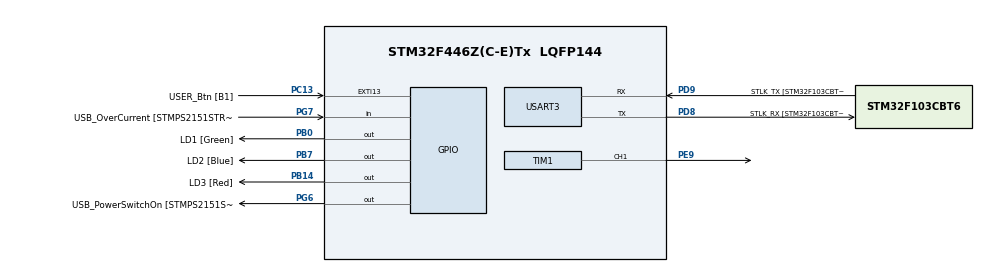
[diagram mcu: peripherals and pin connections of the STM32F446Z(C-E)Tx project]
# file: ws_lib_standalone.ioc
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Dma.Request0=TIM1_CH1
Dma.TIM1_CH1.0.Direction=DMA_PERIPH_TO_MEMORY
Dma.TIM1_CH1.0.FIFOMode=DMA_FIFOMODE_DISABLE
Dma.TIM1_CH1.0.Instance=DMA2_Stream1
Dma.TIM1_CH1.0.MemDataAlignment=DMA_MDATAALIGN_HALFWORD
Dma.TIM1_CH1.0.MemInc=DMA_MINC_ENABLE
Dma.TIM1_CH1.0.Mode=DMA_NORMAL
Dma.TIM1_CH1.0.PeriphDataAlignment=DMA_PDATAALIGN_HALFWORD
Dma.TIM1_CH1.0.PeriphInc=DMA_PINC_DISABLE
Dma.TIM1_CH1.0.Priority=DMA_PRIORITY_LOW
Mcu.Family=STM32F4
Mcu.Name=STM32F446Z(C-E)Tx
Mcu.Package=LQFP144
NVIC.DMA2_Stream1_IRQn=true\:0\:0\:false\:false\:true\:false\:true
NVIC.PriorityGroup=NVIC_PRIORITYGROUP_4
PA10.GPIO_Label=USB_ID
PA10.Signal=USB_OTG_FS_ID
PA11.GPIO_Label=USB_DM
PA11.Signal=USB_OTG_FS_DM
PA12.GPIO_Label=USB_DP
PA12.Signal=USB_OTG_FS_DP
PA13.GPIO_Label=TMS
PA13.Mode=Serial_Wire
PA13.Signal=SYS_JTMS-SWDIO
PA14.GPIO_Label=TCK
PA14.Mode=Serial_Wire
PA14.Signal=SYS_JTCK-SWCLK
PA8.GPIO_Label=USB_SOF [TP1]
PA8.Signal=USB_OTG_FS_SOF
PA9.GPIO_Label=USB_VBUS
PA9.Signal=USB_OTG_FS_VBUS
PB0.GPIO_Label=LD1 [Green]
PB0.Signal=GPIO_Output
PB14.GPIO_Label=LD3 [Red]
PB14.Signal=GPIO_Output
PB7.GPIO_Label=LD2 [Blue]
PB7.Signal=GPIO_Output
PC13.GPIO_Label=USER_Btn [B1]
PC13.Signal=GPXTI13
PC14-OSC32_IN.Mode=LSE-External-Oscillator
PC14-OSC32_IN.Signal=RCC_OSC32_IN
PC15-OSC32_OUT.Mode=LSE-External-Oscillator
PC15-OSC32_OUT.Signal=RCC_OSC32_OUT
PD8.GPIO_Label=STLK_RX [STM32F103CBT6_PA3]
PD8.Mode=Asynchronous
PD8.Signal=USART3_TX
PD9.GPIO_Label=STLK_TX [STM32F103CBT6_PA2]
PD9.Mode=Asynchronous
PD9.Signal=USART3_RX
PE9.Signal=S_TIM1_CH1
PG6.GPIO_Label=USB_PowerSwitchOn [STMPS2151STR_EN]
PG6.Signal=GPIO_Output
PG7.GPIO_Label=USB_OverCurrent [STMPS2151STR_FAULT]
PG7.Signal=GPIO_Input
PH0-OSC_IN.GPIO_Label=MCO [STM32F103CBT6_PA8]
PH0-OSC_IN.Mode=HSE-External-Clock-Source
PH0-OSC_IN.Signal=RCC_OSC_IN
PH1-OSC_OUT.Mode=HSE-External-Clock-Source
PH1-OSC_OUT.Signal=RCC_OSC_OUT
ProjectManager.HeapSize=0x200
ProjectManager.StackSize=0x400
ProjectManager.TargetToolchain=STM32CubeIDE
RCC.48MHZClocksFreq_Value=24000000
RCC.AHBFreq_Value=160000000
RCC.APB1CLKDivider=RCC_HCLK_DIV4
RCC.APB1Freq_Value=40000000
RCC.APB1TimFreq_Value=80000000
RCC.APB2CLKDivider=RCC_HCLK_DIV2
RCC.APB2Freq_Value=80000000
RCC.APB2TimFreq_Value=160000000
RCC.CortexFreq_Value=160000000
RCC.HCLKFreq_Value=160000000
RCC.HSE_VALUE=8000000
RCC.HSI_VALUE=16000000
RCC.PLLM=4
RCC.PLLMUL=RCC_PLL_MUL9
RCC.PLLN=160
RCC.PLLQ=7
RCC.PLLSourceVirtual=RCC_PLLSOURCE_HSE
RCC.PRESCALERUSB=RCC_USBCLKSOURCE_PLL_DIV1_5
RCC.SYSCLKFreq_VALUE=160000000
RCC.SYSCLKSource=RCC_SYSCLKSOURCE_PLLCLK
RCC.SYSCLKSourceVirtual=RCC_SYSCLKSOURCE_PLLCLK
RCC.USBFreq_Value=45714285.71428572
RCC.VCOOutputFreq_Value=320000000
SH.S_TIM1_CH1.0=TIM1_CH1,PWM Generation1 CH1
TIM1.Channel-PWM\ Generation1\ CH1=TIM_CHANNEL_1
USART3.VirtualMode=VM_ASYNC
VP_TIM1_VS_ClockSourceINT.Mode=Internal
board=NUCLEO-F446ZE

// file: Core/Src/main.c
/* USER CODE BEGIN Header */
/**
  ******************************************************************************
  * @file           : main.c
  * @brief          : Main program body
  ******************************************************************************
  * @attention
  *
  * <h2><center>&copy; Copyright (c) 2020 STMicroelectronics.
  * All rights reserved.</center></h2>
  *
  * This software component is licensed by ST under BSD 3-Clause license,
  * the "License"; You may not use this file except in compliance with the
  * License. You may obtain a copy of the License at:
  *                        opensource.org/licenses/BSD-3-Clause
  *
  ******************************************************************************
  */
/* USER CODE END Header */

#include "main.h"

/* USER CODE BEGIN Includes */
#include "stdio.h"
#include "WS2812_Lib.h"
/* USER CODE END Includes */

TIM_HandleTypeDef htim1;
DMA_HandleTypeDef hdma_tim1_ch1;

UART_HandleTypeDef huart3;

void SystemClock_Config(void);
static void MX_GPIO_Init(void);
static void MX_DMA_Init(void);
static void MX_USART3_UART_Init(void);
static void MX_TIM1_Init(void);
/* USER CODE BEGIN PFP */
static void MX_DMA_Init(void);
static void MX_TIM1_Init(void);
/* USER CODE END PFP */

/* USER CODE BEGIN 0 */
int _write(int file, char *ptr, int len){
	int i=0;
	for (i=0; i<len; i++){
		ITM_SendChar((*ptr++));
	}
	return len;
}
/* USER CODE END 0 */

int main(void)
{

  /* MCU Configuration--------------------------------------------------------*/

  /* Reset of all peripherals, Initializes the Flash interface and the Systick. */
  HAL_Init();

  /* Configure the system clock */
  SystemClock_Config();

  /* Initialize all configured peripherals */
  MX_GPIO_Init();
  MX_DMA_Init();
  MX_USART3_UART_Init();
  MX_TIM1_Init();
  /* USER CODE BEGIN 2 */

	printf("led attempt2 function called\n");

	  //This uses the WS2812 instead of WS2812b
	  uint8_t inc =0;
	  WS2812_HSV_t hsv_color;

	  hsv_color.h = 240;
	  hsv_color.v = 5;
	  hsv_color.s = 255;
	  WS2812_Clear();
  /* USER CODE END 2 */

  /* Infinite loop */
  while (1)
  {

    /* USER CODE BEGIN 3 */
	  HAL_GPIO_TogglePin(LD2_GPIO_Port, LD2_Pin);

	  WS2812_All_HSV(hsv_color,1);
	  HAL_Delay(1000);
	  //WS2812_Clear();
	  //HAL_Delay(1000);
		//WS2812_Shift_Right(0);
		//WS2812_One_HSV(0, hsv_color, 1);

		//hsv_color.h=(hsv_color.h > 339)?0: hsv_color.h + 20;

		//osDelay(150);
	  //HAL_Delay(250);
  }
  /* USER CODE END 3 */
}

void SystemClock_Config(void)
{
  RCC_OscInitTypeDef RCC_OscInitStruct = {0};
  RCC_ClkInitTypeDef RCC_ClkInitStruct = {0};

  /** Configure the main internal regulator output voltage
  */
  __HAL_RCC_PWR_CLK_ENABLE();
  __HAL_PWR_VOLTAGESCALING_CONFIG(PWR_REGULATOR_VOLTAGE_SCALE1);
  /** Initializes the CPU, AHB and APB busses clocks
  */
//  RCC_OscInitStruct.OscillatorType = RCC_OSCILLATORTYPE_HSE;
//  RCC_OscInitStruct.HSEState = RCC_HSE_BYPASS;
//  RCC_OscInitStruct.PLL.PLLState = RCC_PLL_ON;
//  RCC_OscInitStruct.PLL.PLLSource = RCC_PLLSOURCE_HSE;
//  RCC_OscInitStruct.PLL.PLLM = 4;
//  RCC_OscInitStruct.PLL.PLLN = 160;
//  RCC_OscInitStruct.PLL.PLLP = RCC_PLLP_DIV2;
//  RCC_OscInitStruct.PLL.PLLQ = 7;
//  RCC_OscInitStruct.PLL.PLLR = 2;
  RCC_OscInitStruct.OscillatorType = RCC_OSCILLATORTYPE_HSI;
  RCC_OscInitStruct.HSIState = RCC_HSI_ON;
  RCC_OscInitStruct.HSICalibrationValue = RCC_HSICALIBRATION_DEFAULT;
  RCC_OscInitStruct.PLL.PLLState = RCC_PLL_ON;
  RCC_OscInitStruct.PLL.PLLSource = RCC_PLLSOURCE_HSI;
  RCC_OscInitStruct.PLL.PLLM = 8;
  RCC_OscInitStruct.PLL.PLLN = 160;
  RCC_OscInitStruct.PLL.PLLP = RCC_PLLP_DIV2;
  RCC_OscInitStruct.PLL.PLLQ = 5;
  RCC_OscInitStruct.PLL.PLLR = 4;
  if (HAL_RCC_OscConfig(&RCC_OscInitStruct) != HAL_OK)
  {
    Error_Handler();
  }
  /** Initializes the CPU, AHB and APB busses clocks
  */
//  RCC_ClkInitStruct.ClockType = RCC_CLOCKTYPE_HCLK|RCC_CLOCKTYPE_SYSCLK
//                              |RCC_CLOCKTYPE_PCLK1|RCC_CLOCKTYPE_PCLK2;
//  RCC_ClkInitStruct.SYSCLKSource = RCC_SYSCLKSOURCE_PLLCLK;
//  RCC_ClkInitStruct.AHBCLKDivider = RCC_SYSCLK_DIV1;
//  RCC_ClkInitStruct.APB1CLKDivider = RCC_HCLK_DIV4;
//  RCC_ClkInitStruct.APB2CLKDivider = RCC_HCLK_DIV2;

  RCC_ClkInitStruct.ClockType = RCC_CLOCKTYPE_HCLK|RCC_CLOCKTYPE_SYSCLK
                              |RCC_CLOCKTYPE_PCLK1|RCC_CLOCKTYPE_PCLK2;
  RCC_ClkInitStruct.SYSCLKSource = RCC_SYSCLKSOURCE_PLLCLK;
  RCC_ClkInitStruct.AHBCLKDivider = RCC_SYSCLK_DIV1;
  RCC_ClkInitStruct.APB1CLKDivider = RCC_HCLK_DIV16;
  RCC_ClkInitStruct.APB2CLKDivider = RCC_HCLK_DIV4;

  if (HAL_RCC_ClockConfig(&RCC_ClkInitStruct, FLASH_LATENCY_5) != HAL_OK)
  {
    Error_Handler();
  }
}

static void MX_TIM1_Init(void)
{

	  TIM_MasterConfigTypeDef sMasterConfig = {0};
	  TIM_OC_InitTypeDef sConfigOC = {0};
	  TIM_BreakDeadTimeConfigTypeDef sBreakDeadTimeConfig = {0};

	  htim1.Instance = TIM1;
	  htim1.Init.Prescaler = 0;
	  htim1.Init.CounterMode = TIM_COUNTERMODE_UP;
	  htim1.Init.Period = 100-1;
	  htim1.Init.ClockDivision = TIM_CLOCKDIVISION_DIV1;
	  //htim1.Init.RepetitionCounter = 255;
	  htim1.Init.AutoReloadPreload = TIM_AUTORELOAD_PRELOAD_DISABLE;
	  if (HAL_TIM_PWM_Init(&htim1) != HAL_OK)
	  {
	    Error_Handler();
	  }
	  sMasterConfig.MasterOutputTrigger = TIM_TRGO_RESET;
	  sMasterConfig.MasterSlaveMode = TIM_MASTERSLAVEMODE_DISABLE;
	  if (HAL_TIMEx_MasterConfigSynchronization(&htim1, &sMasterConfig) != HAL_OK)
	  {
	    Error_Handler();
	  }
	  sConfigOC.OCMode = TIM_OCMODE_PWM1;
	  sConfigOC.Pulse = 0;
	  sConfigOC.OCPolarity = TIM_OCPOLARITY_HIGH;
	  sConfigOC.OCNPolarity = TIM_OCNPOLARITY_HIGH;
	  sConfigOC.OCFastMode = TIM_OCFAST_DISABLE;
	  sConfigOC.OCIdleState = TIM_OCIDLESTATE_RESET;
	  sConfigOC.OCNIdleState = TIM_OCNIDLESTATE_RESET;
	  if (HAL_TIM_PWM_ConfigChannel(&htim1, &sConfigOC, TIM_CHANNEL_1) != HAL_OK)
	  {
	    Error_Handler();
	  }
	  sBreakDeadTimeConfig.OffStateRunMode = TIM_OSSR_DISABLE;
	  sBreakDeadTimeConfig.OffStateIDLEMode = TIM_OSSI_DISABLE;
	  sBreakDeadTimeConfig.LockLevel = TIM_LOCKLEVEL_OFF;
	  sBreakDeadTimeConfig.DeadTime = 0;
	  sBreakDeadTimeConfig.BreakState = TIM_BREAK_DISABLE;
	  sBreakDeadTimeConfig.BreakPolarity = TIM_BREAKPOLARITY_HIGH;
	  sBreakDeadTimeConfig.AutomaticOutput = TIM_AUTOMATICOUTPUT_DISABLE;
	  if (HAL_TIMEx_ConfigBreakDeadTime(&htim1, &sBreakDeadTimeConfig) != HAL_OK)
	  {
	    Error_Handler();
	  }
  HAL_TIM_MspPostInit(&htim1);

}

static void MX_USART3_UART_Init(void)
{

  huart3.Instance = USART3;
  huart3.Init.BaudRate = 115200;
  huart3.Init.WordLength = UART_WORDLENGTH_8B;
  huart3.Init.StopBits = UART_STOPBITS_1;
  huart3.Init.Parity = UART_PARITY_NONE;
  huart3.Init.Mode = UART_MODE_TX_RX;
  huart3.Init.HwFlowCtl = UART_HWCONTROL_NONE;
  huart3.Init.OverSampling = UART_OVERSAMPLING_16;
  if (HAL_UART_Init(&huart3) != HAL_OK)
  {
    Error_Handler();
  }

}

static void MX_DMA_Init(void)
{

  /* DMA controller clock enable */
  __HAL_RCC_DMA2_CLK_ENABLE();

  /* DMA interrupt init */
  /* DMA2_Stream1_IRQn interrupt configuration */
  HAL_NVIC_SetPriority(DMA2_Stream1_IRQn, 0, 0);
  HAL_NVIC_EnableIRQ(DMA2_Stream1_IRQn);

}

static void MX_GPIO_Init(void)
{
  GPIO_InitTypeDef GPIO_InitStruct = {0};

  /* GPIO Ports Clock Enable */
  __HAL_RCC_GPIOC_CLK_ENABLE();
  __HAL_RCC_GPIOH_CLK_ENABLE();
  __HAL_RCC_GPIOB_CLK_ENABLE();
  __HAL_RCC_GPIOE_CLK_ENABLE();
  __HAL_RCC_GPIOD_CLK_ENABLE();
  __HAL_RCC_GPIOG_CLK_ENABLE();
  __HAL_RCC_GPIOA_CLK_ENABLE();

  /*Configure GPIO pin Output Level */
  HAL_GPIO_WritePin(GPIOB, LD1_Pin|LD3_Pin|LD2_Pin, GPIO_PIN_RESET);

  /*Configure GPIO pin Output Level */
  HAL_GPIO_WritePin(USB_PowerSwitchOn_GPIO_Port, USB_PowerSwitchOn_Pin, GPIO_PIN_RESET);

  /*Configure GPIO pin : USER_Btn_Pin */
  GPIO_InitStruct.Pin = USER_Btn_Pin;
  GPIO_InitStruct.Mode = GPIO_MODE_IT_RISING;
  GPIO_InitStruct.Pull = GPIO_NOPULL;
  HAL_GPIO_Init(USER_Btn_GPIO_Port, &GPIO_InitStruct);

  /*Configure GPIO pins : LD1_Pin LD3_Pin LD2_Pin */
  GPIO_InitStruct.Pin = LD1_Pin|LD3_Pin|LD2_Pin;
  GPIO_InitStruct.Mode = GPIO_MODE_OUTPUT_PP;
  GPIO_InitStruct.Pull = GPIO_NOPULL;
  GPIO_InitStruct.Speed = GPIO_SPEED_FREQ_LOW;
  HAL_GPIO_Init(GPIOB, &GPIO_InitStruct);

  /*Configure GPIO pin : USB_PowerSwitchOn_Pin */
  GPIO_InitStruct.Pin = USB_PowerSwitchOn_Pin;
  GPIO_InitStruct.Mode = GPIO_MODE_OUTPUT_PP;
  GPIO_InitStruct.Pull = GPIO_NOPULL;
  GPIO_InitStruct.Speed = GPIO_SPEED_FREQ_LOW;
  HAL_GPIO_Init(USB_PowerSwitchOn_GPIO_Port, &GPIO_InitStruct);

  /*Configure GPIO pin : USB_OverCurrent_Pin */
  GPIO_InitStruct.Pin = USB_OverCurrent_Pin;
  GPIO_InitStruct.Mode = GPIO_MODE_INPUT;
  GPIO_InitStruct.Pull = GPIO_NOPULL;
  HAL_GPIO_Init(USB_OverCurrent_GPIO_Port, &GPIO_InitStruct);

  /*Configure GPIO pins : USB_SOF_Pin USB_ID_Pin USB_DM_Pin USB_DP_Pin */
  GPIO_InitStruct.Pin = USB_SOF_Pin|USB_ID_Pin|USB_DM_Pin|USB_DP_Pin;
  GPIO_InitStruct.Mode = GPIO_MODE_AF_PP;
  GPIO_InitStruct.Pull = GPIO_NOPULL;
  GPIO_InitStruct.Speed = GPIO_SPEED_FREQ_VERY_HIGH;
  GPIO_InitStruct.Alternate = GPIO_AF10_OTG_FS;
  HAL_GPIO_Init(GPIOA, &GPIO_InitStruct);

  /*Configure GPIO pin : USB_VBUS_Pin */
  GPIO_InitStruct.Pin = USB_VBUS_Pin;
  GPIO_InitStruct.Mode = GPIO_MODE_INPUT;
  GPIO_InitStruct.Pull = GPIO_NOPULL;
  HAL_GPIO_Init(USB_VBUS_GPIO_Port, &GPIO_InitStruct);

}

void Error_Handler(void)
{
}

/************************ (C) COPYRIGHT STMicroelectronics *****END OF FILE****/
